VERSION 5.7 ;
  NOWIREEXTENSIONATPIN ON ;
  DIVIDERCHAR "/" ;
  BUSBITCHARS "[]" ;
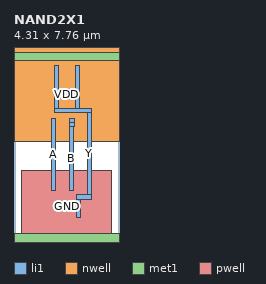
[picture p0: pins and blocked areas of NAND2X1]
MACRO NAND2X1
  CLASS CORE ;
  FOREIGN NAND2X1 ;
  ORIGIN 0.000 0.000 ;
  SIZE 4.310 BY 7.760 ;
  SYMMETRY X Y ;
  SITE unitrh ;
  PIN Y
    DIRECTION OUTPUT ;
    USE SIGNAL ;
    ANTENNADIFFAREA 1.351900 ;
    PORT
      LAYER li1 ;
        RECT 1.635 5.465 1.805 7.200 ;
        RECT 2.515 5.465 2.685 7.200 ;
        RECT 1.635 5.295 3.165 5.465 ;
        RECT 2.995 1.920 3.165 5.295 ;
        RECT 2.555 1.750 3.165 1.920 ;
        RECT 2.555 1.015 2.725 1.750 ;
    END
  END Y
  PIN A
    DIRECTION INPUT ;
    USE SIGNAL ;
    ANTENNAGATEAREA 1.033250 ;
    PORT
      LAYER li1 ;
        RECT 1.515 2.095 1.685 5.045 ;
    END
  END A
  PIN B
    DIRECTION INPUT ;
    USE SIGNAL ;
    ANTENNAGATEAREA 1.027250 ;
    PORT
      LAYER li1 ;
        RECT 2.285 4.890 2.455 5.045 ;
        RECT 2.255 4.715 2.455 4.890 ;
        RECT 2.255 2.095 2.425 4.715 ;
    END
  END B
  PIN VDD
    DIRECTION INOUT ;
    USE POWER ;
    SHAPE ABUTMENT ;
    PORT
      LAYER nwell ;
        RECT 0.000 4.110 4.310 7.940 ;
      LAYER met1 ;
        RECT 0.000 7.410 4.310 7.760 ;
    END
  END VDD
  PIN GND
    DIRECTION INOUT ;
    USE GROUND ;
    SHAPE ABUTMENT ;
    PORT
      LAYER pwell ;
        RECT 0.320 0.000 3.990 2.900 ;
      LAYER met1 ;
        RECT 0.000 0.000 4.310 0.350 ;
    END
  END GND
  OBS
      LAYER li1 ;
        RECT 0.000 7.410 4.310 7.760 ;
        RECT 0.320 4.290 0.660 7.410 ;
        RECT 1.195 5.315 1.365 7.410 ;
        RECT 2.075 5.735 2.245 7.410 ;
        RECT 2.955 5.735 3.125 7.410 ;
        RECT 3.650 4.290 3.990 7.410 ;
        RECT 0.320 0.350 0.660 2.900 ;
        RECT 1.100 1.845 1.270 1.925 ;
        RECT 2.070 1.845 2.240 1.925 ;
        RECT 1.100 1.675 2.240 1.845 ;
        RECT 1.100 0.545 1.270 1.675 ;
        RECT 1.585 0.350 1.755 1.300 ;
        RECT 2.070 0.795 2.240 1.675 ;
        RECT 3.040 0.795 3.210 1.565 ;
        RECT 2.070 0.625 3.210 0.795 ;
        RECT 2.070 0.545 2.240 0.625 ;
        RECT 3.040 0.545 3.210 0.625 ;
        RECT 3.650 0.350 3.990 2.900 ;
        RECT 0.000 0.000 4.310 0.350 ;
      LAYER mcon ;
        RECT 0.775 7.495 0.945 7.665 ;
        RECT 1.145 7.495 1.315 7.665 ;
        RECT 1.515 7.495 1.685 7.665 ;
        RECT 1.885 7.495 2.055 7.665 ;
        RECT 2.255 7.495 2.425 7.665 ;
        RECT 2.625 7.495 2.795 7.665 ;
        RECT 2.995 7.495 3.165 7.665 ;
        RECT 3.365 7.495 3.535 7.665 ;
        RECT 0.775 0.095 0.945 0.265 ;
        RECT 1.145 0.095 1.315 0.265 ;
        RECT 1.515 0.095 1.685 0.265 ;
        RECT 1.885 0.095 2.055 0.265 ;
        RECT 2.255 0.095 2.425 0.265 ;
        RECT 2.625 0.095 2.795 0.265 ;
        RECT 2.995 0.095 3.165 0.265 ;
        RECT 3.365 0.095 3.535 0.265 ;
  END
END NAND2X1
END LIBRARY

